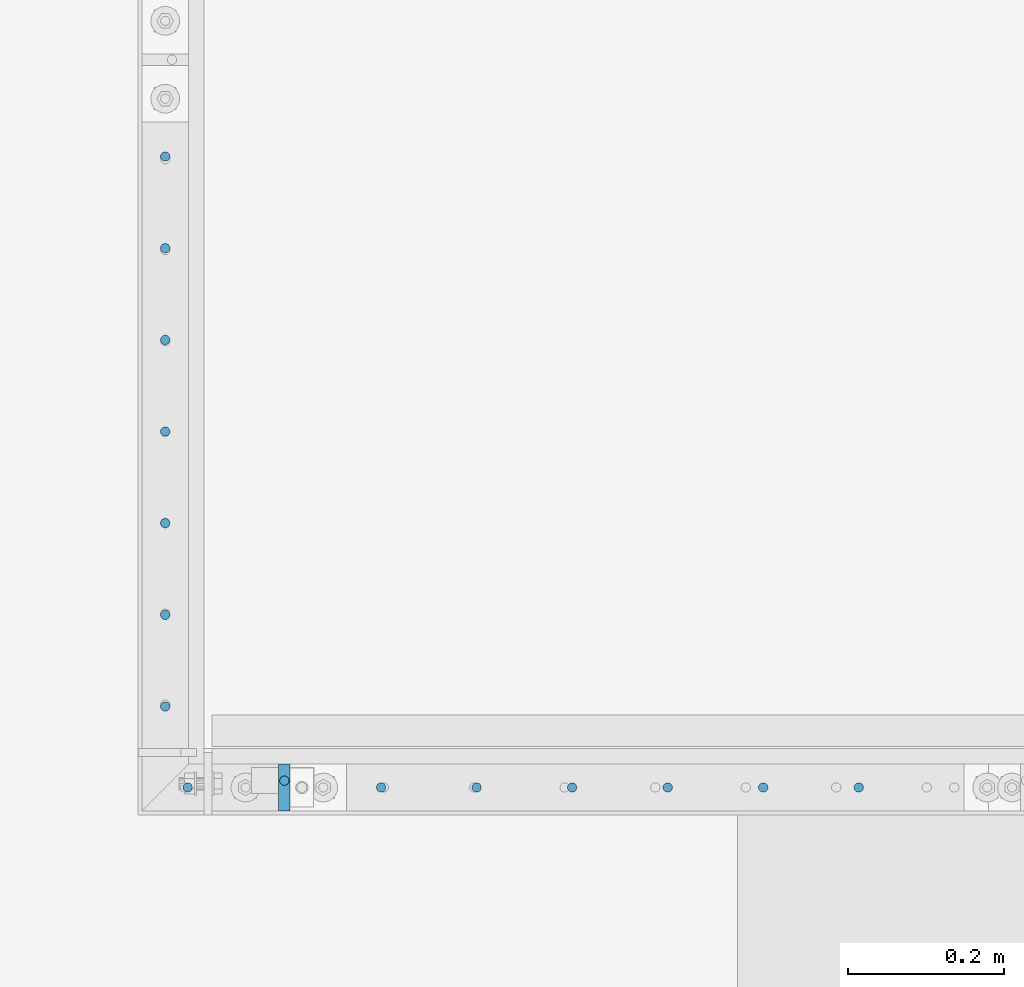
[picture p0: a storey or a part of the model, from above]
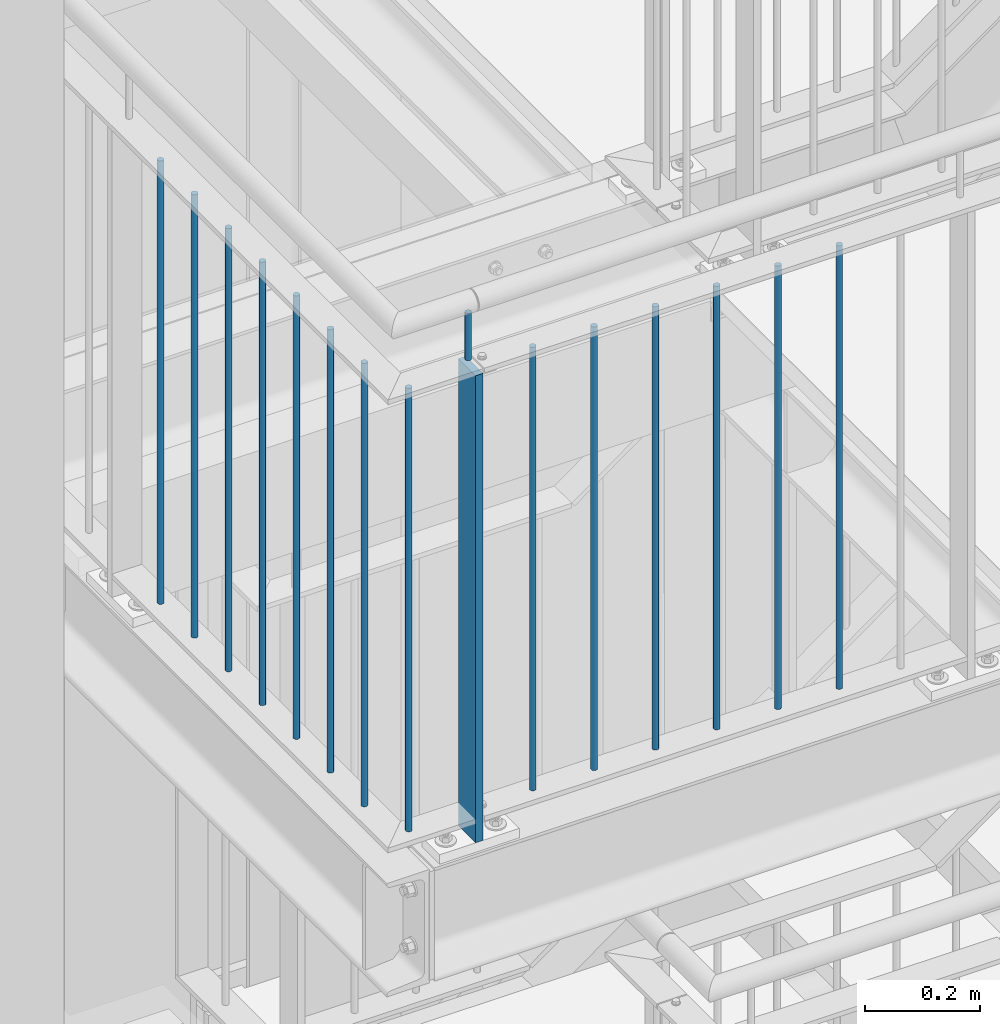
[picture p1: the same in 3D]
Properties of the parts of a building model (IFC2X3)

# File
Description: ViewDefinition[CoordinationView_V2.0]
File name: Treppenturm an Kinderklinik N?rnberg_ifc2x3.ifc
Time: 2026-07-12T00:24:05
Written by: IFC Toolkit 2.0.26.0
Made in: Advance Steel 2024

# IfcBuildingStorey, Default Storey
In: Struktur 1
Elevation: 0 mm

# IfcBeam: - (30)
In: Default Storey
Description: RO33.7X2.6; Material: S235JR
ProfileProperties - SectionFamily: Pipe nach DIN; Section: RO33.7X2.6

# IfcBeam: BottomLanding#1 (11)
In: Default Storey
Description: U240; Material: S235JR
ProfileProperties - SectionFamily: Channels DIN18800-1; Section: U240

# IfcBeam: BottomLanding#2 (11)
In: Default Storey
Description: U240; Material: S235JR
ProfileProperties - SectionFamily: Channels DIN18800-1; Section: U240

# IfcBeam: BottomLanding#3 (22)
In: Default Storey
Description: L40X4; Material: S235JR
ProfileProperties - SectionFamily: Angle_eq DIN18800-1; Section: L40X4

# IfcBeam: Elbow#0 (5)
In: Default Storey
Description: RO42.4X3.2; Material: S235JR

# IfcBeam: Elbow#1 (6)
In: Default Storey
Description: RO42.4X3.2; Material: S235JR

# IfcBeam: Gel?nder (13)
In: Default Storey
Description: RO42.4X3.2; Material: S235JR
Pset_BeamCommon - Slope: 0 deg; IsExternal: no; LoadBearing: no
ProfileProperties - SectionFamily: Pipe nach DIN; Section: RO42.4X3.2
Name | Reference | Span (mm)
Gel?nder | 80 | 2854.8
Gel?nder | 79 | 1242.04
5 x Gel?nder | 66 | 2854.8
5 x Gel?nder | 65 | 1242.04
Gel?nder | 93 | 1847

# IfcBeam: Girder (45)
In: Default Storey
Material: S235JR
Pset_BeamCommon - Slope: 0 deg; IsExternal: no; LoadBearing: no
Name | Description = Section | Reference | Span (mm) | SectionFamily
5 x Girder | U100 | 34 | 1139 | Channels DIN18800-1
Girder | IPE240 | 20 | 3963.5 | IPE DIN18800-1
Girder | U240 | 39 | 1605 | Channels DIN18800-1
Girder | U240 | 40 | 1260 | Channels DIN18800-1
11 x Girder | HEA200 | 17 | 2940 | HEA DIN18800-1
Girder | HEA200 | 18 | 2940 | HEA DIN18800-1
12 x Girder | RO82.5x3.2 (Mannesmann) | 21 | 3363.5 | Pipe nach mannesmann
5 x Girder | U240 | 35 | 3120 | Channels DIN18800-1
Girder | U240 | 37 | 2950 | Channels DIN18800-1
Girder | U240 | 38 | 2900 | Channels DIN18800-1
5 x Girder | U240 | 36 | 2900 | Channels DIN18800-1
Girder | IPE240 | 19 | 1596.75 | IPE DIN18800-1

# IfcBeam: Railing_Handrail_Landing#0 (7)
In: Default Storey
Description: RO42.4X3.2; Material: S235JR
ProfileProperties - SectionFamily: Pipe nach DIN; Section: RO42.4X3.2

# IfcBeam: Railing_Handrail_Landing#2 (16)
In: Default Storey
Description: RO42.4X3.2; Material: S235JR
ProfileProperties - SectionFamily: Pipe nach DIN; Section: RO42.4X3.2

# IfcBeam: Railing_Handrail_Landing#3 (3)
In: Default Storey
Description: RO42.4X3.2; Material: S235JR
ProfileProperties - SectionFamily: Pipe nach DIN; Section: RO42.4X3.2

# IfcBeam: Railing_Handrail_Landing#4 (24)
In: Default Storey
Description: RO42.4X3.2; Material: S235JR
ProfileProperties - SectionFamily: Pipe nach DIN; Section: RO42.4X3.2

# IfcBeam: Railing_Handrail_Landing#5 (22)
In: Default Storey
Description: RO42.4X3.2; Material: S235JR
ProfileProperties - SectionFamily: Pipe nach DIN; Section: RO42.4X3.2

# IfcBeam: Railing_Handrail_Landing#6 (10)
In: Default Storey
Description: RO42.4X3.2; Material: S235JR
ProfileProperties - SectionFamily: Pipe nach DIN; Section: RO42.4X3.2

# IfcBeam: Railing_Handrail_Landing#7 (2)
In: Default Storey
Description: RO42.4X3.2; Material: S235JR
ProfileProperties - SectionFamily: Pipe nach DIN; Section: RO42.4X3.2

# IfcBeam: Railing_Handrail_Landing#8 (10)
In: Default Storey
Description: RO42.4X3.2; Material: S235JR
ProfileProperties - SectionFamily: Pipe nach DIN; Section: RO42.4X3.2

# IfcBeam: Railing_Kneerail_Landing#0 (20)
In: Default Storey
Description: FL60X10; Material: S235JR
ProfileProperties - SectionFamily: Flat nach DIN; Section: FL60X10

# IfcBeam: Railing_Kneerail_Landing#1 (10)
In: Default Storey
Description: FL60X10; Material: S235JR
ProfileProperties - SectionFamily: Flat nach DIN; Section: FL60X10

# IfcBeam: Railing_Kneerail_Landing#10 (7)
In: Default Storey
Description: FL60X10; Material: S235JR
ProfileProperties - SectionFamily: Flat nach DIN; Section: FL60X10

# IfcBeam: Railing_Kneerail_Landing#1000 (12)
In: Default Storey
Description: FL60X10; Material: S235JR
ProfileProperties - SectionFamily: Flat nach DIN; Section: FL60X10

# IfcBeam: Railing_Kneerail_Landing#1001 (4)
In: Default Storey
Description: FL60X10; Material: S235JR
ProfileProperties - SectionFamily: Flat nach DIN; Section: FL60X10

# IfcBeam: Railing_Kneerail_Landing#1003
In: Default Storey
Description: FL60X10; Material: S235JR
ProfileProperties - SectionFamily: Flat nach DIN; Section: FL60X10

# IfcBeam: Railing_Kneerail_Landing#1004 (3)
In: Default Storey
Description: FL60X10; Material: S235JR
ProfileProperties - SectionFamily: Flat nach DIN; Section: FL60X10

# IfcBeam: Railing_Kneerail_Landing#1005 (21)
In: Default Storey
Description: FL60X10; Material: S235JR
ProfileProperties - SectionFamily: Flat nach DIN; Section: FL60X10

# IfcBeam: Railing_Kneerail_Landing#1006 (18)
In: Default Storey
Description: FL60X10; Material: S235JR
ProfileProperties - SectionFamily: Flat nach DIN; Section: FL60X10

# IfcBeam: Railing_Kneerail_Landing#1007 (6)
In: Default Storey
Description: FL60X10; Material: S235JR
ProfileProperties - SectionFamily: Flat nach DIN; Section: FL60X10

# IfcBeam: Railing_Kneerail_Landing#1008 (3)
In: Default Storey
Description: FL60X10; Material: S235JR
ProfileProperties - SectionFamily: Flat nach DIN; Section: FL60X10

# IfcBeam: Railing_Kneerail_Landing#1011 (3)
In: Default Storey
Description: FL60X10; Material: S235JR
ProfileProperties - SectionFamily: Flat nach DIN; Section: FL60X10

# IfcBeam: Railing_Kneerail_Landing#1012 (6)
In: Default Storey
Description: FL60X10; Material: S235JR
ProfileProperties - SectionFamily: Flat nach DIN; Section: FL60X10

# IfcBeam: Railing_Kneerail_Landing#1014 (4)
In: Default Storey
Description: FL60X10; Material: S235JR
ProfileProperties - SectionFamily: Flat nach DIN; Section: FL60X10

# IfcBeam: Railing_Kneerail_Landing#1018 (8)
In: Default Storey
Description: FL60X10; Material: S235JR
ProfileProperties - SectionFamily: Flat nach DIN; Section: FL60X10

# IfcBeam: Railing_Kneerail_Landing#1019
In: Default Storey
Description: FL60X10; Material: S235JR
ProfileProperties - SectionFamily: Flat nach DIN; Section: FL60X10

# IfcBeam: Railing_Kneerail_Landing#1020 (4)
In: Default Storey
Description: FL60X10; Material: S235JR
ProfileProperties - SectionFamily: Flat nach DIN; Section: FL60X10

# IfcBeam: Railing_Kneerail_Landing#1021 (5)
In: Default Storey
Description: FL60X10; Material: S235JR
ProfileProperties - SectionFamily: Flat nach DIN; Section: FL60X10

# IfcBeam: Railing_Kneerail_Landing#11 (6)
In: Default Storey
Description: FL60X10; Material: S235JR
ProfileProperties - SectionFamily: Flat nach DIN; Section: FL60X10

# IfcBeam: Railing_Kneerail_Landing#12 (5)
In: Default Storey
Description: FL60X10; Material: S235JR
ProfileProperties - SectionFamily: Flat nach DIN; Section: FL60X10

# IfcBeam: Railing_Kneerail_Landing#13 (5)
In: Default Storey
Description: FL60X10; Material: S235JR
ProfileProperties - SectionFamily: Flat nach DIN; Section: FL60X10

# IfcBeam: Railing_Kneerail_Landing#14 (4)
In: Default Storey
Description: FL60X10; Material: S235JR
ProfileProperties - SectionFamily: Flat nach DIN; Section: FL60X10

# IfcBeam: Railing_Kneerail_Landing#16
In: Default Storey
Description: FL60X10; Material: S235JR
ProfileProperties - SectionFamily: Flat nach DIN; Section: FL60X10

# IfcBeam: Railing_Kneerail_Landing#17
In: Default Storey
Description: FL60X10; Material: S235JR
ProfileProperties - SectionFamily: Flat nach DIN; Section: FL60X10

# IfcBeam: Railing_Kneerail_Landing#18 (6)
In: Default Storey
Description: FL60X10; Material: S235JR
ProfileProperties - SectionFamily: Flat nach DIN; Section: FL60X10

# IfcBeam: Railing_Kneerail_Landing#19 (6)
In: Default Storey
Description: FL60X10; Material: S235JR
ProfileProperties - SectionFamily: Flat nach DIN; Section: FL60X10

# IfcBeam: Railing_Kneerail_Landing#20 (5)
In: Default Storey
Description: FL60X10; Material: S235JR
ProfileProperties - SectionFamily: Flat nach DIN; Section: FL60X10

# IfcBeam: Railing_Kneerail_Landing#21 (5)
In: Default Storey
Description: FL60X10; Material: S235JR
ProfileProperties - SectionFamily: Flat nach DIN; Section: FL60X10

# IfcBeam: Railing_Kneerail_Landing#22 (6)
In: Default Storey
Description: FL60X10; Material: S235JR
ProfileProperties - SectionFamily: Flat nach DIN; Section: FL60X10

# IfcBeam: Railing_Kneerail_Landing#3
In: Default Storey
Description: FL60X10; Material: S235JR
ProfileProperties - SectionFamily: Flat nach DIN; Section: FL60X10

# IfcBeam: Railing_Kneerail_Landing#4 (10)
In: Default Storey
Description: FL60X10; Material: S235JR
ProfileProperties - SectionFamily: Flat nach DIN; Section: FL60X10

# IfcBeam: Railing_Kneerail_Landing#5 (19)
In: Default Storey
Description: FL60X10; Material: S235JR
ProfileProperties - SectionFamily: Flat nach DIN; Section: FL60X10

# IfcBeam: Railing_Kneerail_Landing#6 (24)
In: Default Storey
Description: FL60X10; Material: S235JR
ProfileProperties - SectionFamily: Flat nach DIN; Section: FL60X10

# IfcBeam: Railing_Kneerail_Landing#7 (13)
In: Default Storey
Description: FL60X10; Material: S235JR
ProfileProperties - SectionFamily: Flat nach DIN; Section: FL60X10

# IfcBeam: Railing_Kneerail_Landing#8 (7)
In: Default Storey
Description: FL60X10; Material: S235JR
ProfileProperties - SectionFamily: Flat nach DIN; Section: FL60X10

# IfcBeam: Railing_Kneerail_Landing#9 (6)
In: Default Storey
Description: FL60X10; Material: S235JR
ProfileProperties - SectionFamily: Flat nach DIN; Section: FL60X10

# IfcBeam: Stringer (24)
In: Default Storey
Description: U240; Material: S235JR
Pset_BeamCommon - Slope: 0 deg; IsExternal: no; LoadBearing: no
ProfileProperties - SectionFamily: Channels DIN18800-1; Section: U240
Name | Reference | Span (mm)
Stringer | 54 | 1960.42
Stringer | 53 | 1960.42
Stringer | 50 | 1960.32
Stringer | 49 | 1960.32
Stringer | 57 | 1960.25
Stringer | 58 | 1960.25
Stringer | 61 | 1960.57
Stringer | 62 | 1960.57
Stringer | 56 | 1960.42
Stringer | 55 | 1960.42
Stringer | 60 | 1960.25
Stringer | 59 | 1960.25
Stringer | 64 | 1960.57
Stringer | 63 | 1960.57
Stringer | 52 | 1960.32
Stringer | 51 | 1960.32
Stringer | 46 | 1441.89
Stringer | 45 | 1441.89
Stringer | 42 | 1441.18
Stringer | 41 | 1441.18
Stringer | 43 | 1961.18
Stringer | 44 | 1961.18
Stringer | 48 | 1961.89
Stringer | 47 | 1961.89

# IfcBeam: TopLanding#1 (5)
In: Default Storey
Description: U100; Material: S235JR
ProfileProperties - SectionFamily: Channels DIN18800-1; Section: U100

# IfcBeam: TopLanding#3 (24)
In: Default Storey
Description: L40X4; Material: S235JR
ProfileProperties - SectionFamily: Angle_eq DIN18800-1; Section: L40X4

# IfcBuildingElementProxy: - (216)
In: Default Storey
Material: Kein

# IfcColumn: - (4)
In: Default Storey
Description: HEA120; Material: S235JR
ProfileProperties - SectionFamily: HEA DIN18800-1; Section: HEA120

# IfcColumn: Bar#0 (18)
In: Default Storey
Description: RD12; Material: S235JR
ProfileProperties - SectionFamily: Round nach DIN; Section: RD12

# IfcColumn: Bar#1 (18)
In: Default Storey
Description: RD12; Material: S235JR
ProfileProperties - SectionFamily: Round nach DIN; Section: RD12

# IfcColumn: Bar#10 (6)
In: Default Storey
Description: RD12; Material: S235JR
ProfileProperties - SectionFamily: Round nach DIN; Section: RD12

# IfcColumn: Bar#11 (6)
In: Default Storey
Description: RD12; Material: S235JR
ProfileProperties - SectionFamily: Round nach DIN; Section: RD12

# IfcColumn: Bar#12 (6)
In: Default Storey
Description: RD12; Material: S235JR
ProfileProperties - SectionFamily: Round nach DIN; Section: RD12

# IfcColumn: Bar#13 (6)
In: Default Storey
Description: RD12; Material: S235JR
ProfileProperties - SectionFamily: Round nach DIN; Section: RD12

# IfcColumn: Bar#14 (5)
In: Default Storey
Description: RD12; Material: S235JR
ProfileProperties - SectionFamily: Round nach DIN; Section: RD12

# IfcColumn: Bar#2 (18)
In: Default Storey
Description: RD12; Material: S235JR
ProfileProperties - SectionFamily: Round nach DIN; Section: RD12

# IfcColumn: Bar#3 (10)
In: Default Storey
Description: RD12; Material: S235JR
ProfileProperties - SectionFamily: Round nach DIN; Section: RD12

# IfcColumn: Bar#4 (7)
In: Default Storey
Description: RD12; Material: S235JR
ProfileProperties - SectionFamily: Round nach DIN; Section: RD12

# IfcColumn: Bar#5 (6)
In: Default Storey
Description: RD12; Material: S235JR
ProfileProperties - SectionFamily: Round nach DIN; Section: RD12

# IfcColumn: Bar#6 (6)
In: Default Storey
Description: RD12; Material: S235JR
ProfileProperties - SectionFamily: Round nach DIN; Section: RD12

# IfcColumn: Bar#7 (6)
In: Default Storey
Description: RD12; Material: S235JR
ProfileProperties - SectionFamily: Round nach DIN; Section: RD12

# IfcColumn: Bar#8 (6)
In: Default Storey
Description: RD12; Material: S235JR
ProfileProperties - SectionFamily: Round nach DIN; Section: RD12

# IfcColumn: Bar#9 (6)
In: Default Storey
Description: RD12; Material: S235JR
ProfileProperties - SectionFamily: Round nach DIN; Section: RD12

# IfcColumn: Column (16)
In: Default Storey
Description: HEA200; Material: S235JR
Pset_ColumnCommon - Slope: 0 deg; IsExternal: no; LoadBearing: no
ProfileProperties - SectionFamily: HEA DIN18800-1; Section: HEA200
Name | Reference
Column | 2
Column | 1
Column | 3
Column | 4
Column | 5
Column | 6
Column | 7
Column | 8
Column | 9
Column | 10
Column | 11
Column | 12
Column | 13
Column | 14
Column | 15
Column | 16

# IfcColumn: Railing_Handrail_Landing#0 (2)
In: Default Storey
Description: RO42.4X3.2; Material: S235JR
ProfileProperties - SectionFamily: Pipe nach DIN; Section: RO42.4X3.2

# IfcColumn: Railing_Kneerail_Landing#0 (5)
In: Default Storey
Description: FL60X10; Material: S235JR
ProfileProperties - SectionFamily: Flat nach DIN; Section: FL60X10

# IfcColumn: Railing_Kneerail_Landing#22 (6)
In: Default Storey
Description: FL60X10; Material: S235JR
ProfileProperties - SectionFamily: Flat nach DIN; Section: FL60X10

# IfcColumn: Railing_Kneerail_Landing#8
In: Default Storey
Description: FL60X10; Material: S235JR
ProfileProperties - SectionFamily: Flat nach DIN; Section: FL60X10

# IfcColumn: Railing_Picket_Landing#0 (15)
In: Default Storey
Description: RD12; Material: S235JR
ProfileProperties - SectionFamily: Round nach DIN; Section: RD12

# IfcColumn: Railing_Picket_Landing#1 (8)
In: Default Storey
Description: RD12; Material: S235JR
ProfileProperties - SectionFamily: Round nach DIN; Section: RD12

# IfcColumn: Railing_Picket_Landing#12 (4)
In: Default Storey
Description: RD12; Material: S235JR
ProfileProperties - SectionFamily: Round nach DIN; Section: RD12

# IfcColumn: Railing_Picket_Landing#13 (4)
In: Default Storey
Description: RD12; Material: S235JR
ProfileProperties - SectionFamily: Round nach DIN; Section: RD12

# IfcColumn: Railing_Picket_Landing#14 (4)
In: Default Storey
Description: RD12; Material: S235JR
ProfileProperties - SectionFamily: Round nach DIN; Section: RD12

# IfcColumn: Railing_Picket_Landing#15 (5)
In: Default Storey
Description: RD12; Material: S235JR
ProfileProperties - SectionFamily: Round nach DIN; Section: RD12

# IfcColumn: Railing_Picket_Landing#16 (8)
In: Default Storey
Description: RD12; Material: S235JR
ProfileProperties - SectionFamily: Round nach DIN; Section: RD12

# IfcColumn: Railing_Picket_Landing#17 (8)
In: Default Storey
Description: RD12; Material: S235JR
ProfileProperties - SectionFamily: Round nach DIN; Section: RD12

# IfcColumn: Railing_Picket_Landing#18 (8)
In: Default Storey
Description: RD12; Material: S235JR
ProfileProperties - SectionFamily: Round nach DIN; Section: RD12

# IfcColumn: Railing_Picket_Landing#19 (8)
In: Default Storey
Description: RD12; Material: S235JR
ProfileProperties - SectionFamily: Round nach DIN; Section: RD12

# IfcColumn: Railing_Picket_Landing#2 (8)
In: Default Storey
Description: RD12; Material: S235JR
ProfileProperties - SectionFamily: Round nach DIN; Section: RD12

# IfcColumn: Railing_Picket_Landing#20 (9)
In: Default Storey
Description: RD12; Material: S235JR
ProfileProperties - SectionFamily: Round nach DIN; Section: RD12

# IfcColumn: Railing_Picket_Landing#21 (7)
In: Default Storey
Description: RD12; Material: S235JR
ProfileProperties - SectionFamily: Round nach DIN; Section: RD12

# IfcColumn: Railing_Picket_Landing#22 (7)
In: Default Storey
Description: RD12; Material: S235JR
ProfileProperties - SectionFamily: Round nach DIN; Section: RD12

# IfcColumn: Railing_Picket_Landing#23 (7)
In: Default Storey
Description: RD12; Material: S235JR
ProfileProperties - SectionFamily: Round nach DIN; Section: RD12

# IfcColumn: Railing_Picket_Landing#24 (7)
In: Default Storey
Description: RD12; Material: S235JR
ProfileProperties - SectionFamily: Round nach DIN; Section: RD12

# IfcColumn: Railing_Picket_Landing#25 (7)
In: Default Storey
Description: RD12; Material: S235JR
ProfileProperties - SectionFamily: Round nach DIN; Section: RD12

# IfcColumn: Railing_Picket_Landing#26 (7)
In: Default Storey
Description: RD12; Material: S235JR
ProfileProperties - SectionFamily: Round nach DIN; Section: RD12

# IfcColumn: Railing_Picket_Landing#27 (8)
In: Default Storey
Description: RD12; Material: S235JR
ProfileProperties - SectionFamily: Round nach DIN; Section: RD12

# IfcColumn: Railing_Picket_Landing#28 (6)
In: Default Storey
Description: RD12; Material: S235JR
ProfileProperties - SectionFamily: Round nach DIN; Section: RD12

# IfcColumn: Railing_Picket_Landing#29 (6)
In: Default Storey
Description: RD12; Material: S235JR
ProfileProperties - SectionFamily: Round nach DIN; Section: RD12

# IfcColumn: Railing_Picket_Landing#30 (6)
In: Default Storey
Description: RD12; Material: S235JR
ProfileProperties - SectionFamily: Round nach DIN; Section: RD12

# IfcColumn: Railing_Picket_Landing#31 (6)
In: Default Storey
Description: RD12; Material: S235JR
ProfileProperties - SectionFamily: Round nach DIN; Section: RD12

# IfcColumn: Railing_Picket_Landing#32 (6)
In: Default Storey
Description: RD12; Material: S235JR
ProfileProperties - SectionFamily: Round nach DIN; Section: RD12

# IfcColumn: Railing_Picket_Landing#33 (6)
In: Default Storey
Description: RD12; Material: S235JR
ProfileProperties - SectionFamily: Round nach DIN; Section: RD12

# IfcColumn: Railing_Picket_Landing#34 (6)
In: Default Storey
Description: RD12; Material: S235JR
ProfileProperties - SectionFamily: Round nach DIN; Section: RD12

# IfcColumn: Railing_Picket_Landing#35 (6)
In: Default Storey
Description: RD12; Material: S235JR
ProfileProperties - SectionFamily: Round nach DIN; Section: RD12

# IfcColumn: Railing_Picket_Landing#36 (6)
In: Default Storey
Description: RD12; Material: S235JR
ProfileProperties - SectionFamily: Round nach DIN; Section: RD12

# IfcColumn: Railing_Picket_Landing#37 (6)
In: Default Storey
Description: RD12; Material: S235JR
ProfileProperties - SectionFamily: Round nach DIN; Section: RD12

# IfcColumn: Railing_Picket_Landing#38 (6)
In: Default Storey
Description: RD12; Material: S235JR
ProfileProperties - SectionFamily: Round nach DIN; Section: RD12

# IfcColumn: Railing_Picket_Landing#39 (6)
In: Default Storey
Description: RD12; Material: S235JR
ProfileProperties - SectionFamily: Round nach DIN; Section: RD12

# IfcColumn: Railing_Picket_Landing#40 (6)
In: Default Storey
Description: RD12; Material: S235JR
ProfileProperties - SectionFamily: Round nach DIN; Section: RD12

# IfcColumn: Railing_Picket_Landing#41 (6)
In: Default Storey
Description: RD12; Material: S235JR
ProfileProperties - SectionFamily: Round nach DIN; Section: RD12

# IfcColumn: Railing_Picket_Landing#42 (6)
In: Default Storey
Description: RD12; Material: S235JR
ProfileProperties - SectionFamily: Round nach DIN; Section: RD12

# IfcColumn: Railing_Picket_Landing#43 (6)
In: Default Storey
Description: RD12; Material: S235JR
ProfileProperties - SectionFamily: Round nach DIN; Section: RD12

# IfcColumn: Railing_Picket_Landing#44 (6)
In: Default Storey
Description: RD12; Material: S235JR
ProfileProperties - SectionFamily: Round nach DIN; Section: RD12

# IfcColumn: Railing_Picket_Landing#45 (6)
In: Default Storey
Description: RD12; Material: S235JR
ProfileProperties - SectionFamily: Round nach DIN; Section: RD12

# IfcColumn: Railing_Picket_Landing#46 (6)
In: Default Storey
Description: RD12; Material: S235JR
ProfileProperties - SectionFamily: Round nach DIN; Section: RD12

# IfcColumn: Railing_Picket_Landing#47 (6)
In: Default Storey
Description: RD12; Material: S235JR
ProfileProperties - SectionFamily: Round nach DIN; Section: RD12

# IfcColumn: Railing_Picket_Landing#48 (6)
In: Default Storey
Description: RD12; Material: S235JR
ProfileProperties - SectionFamily: Round nach DIN; Section: RD12

# IfcColumn: Railing_Picket_Landing#49 (6)
In: Default Storey
Description: RD12; Material: S235JR
ProfileProperties - SectionFamily: Round nach DIN; Section: RD12

# IfcColumn: Railing_Picket_Landing#50 (6)
In: Default Storey
Description: RD12; Material: S235JR
ProfileProperties - SectionFamily: Round nach DIN; Section: RD12

# IfcColumn: Railing_Picket_Landing#51 (6)
In: Default Storey
Description: RD12; Material: S235JR
ProfileProperties - SectionFamily: Round nach DIN; Section: RD12

# IfcColumn: Railing_Picket_Landing#52 (6)
In: Default Storey
Description: RD12; Material: S235JR
ProfileProperties - SectionFamily: Round nach DIN; Section: RD12

# IfcColumn: Railing_Picket_Landing#53 (6)
In: Default Storey
Description: RD12; Material: S235JR
ProfileProperties - SectionFamily: Round nach DIN; Section: RD12

# IfcColumn: Railing_Picket_Landing#54 (6)
In: Default Storey
Description: RD12; Material: S235JR
ProfileProperties - SectionFamily: Round nach DIN; Section: RD12

# IfcColumn: Railing_Picket_Landing#55 (5)
In: Default Storey
Description: RD12; Material: S235JR
ProfileProperties - SectionFamily: Round nach DIN; Section: RD12

# IfcColumn: Railing_Picket_Landing#56 (5)
In: Default Storey
Description: RD12; Material: S235JR
ProfileProperties - SectionFamily: Round nach DIN; Section: RD12

# IfcColumn: Railing_Picket_Landing#57 (5)
In: Default Storey
Description: RD12; Material: S235JR
ProfileProperties - SectionFamily: Round nach DIN; Section: RD12

# IfcColumn: Railing_Picket_Landing#58 (5)
In: Default Storey
Description: RD12; Material: S235JR
ProfileProperties - SectionFamily: Round nach DIN; Section: RD12

# IfcColumn: Railing_Picket_Landing#59 (5)
In: Default Storey
Description: RD12; Material: S235JR
ProfileProperties - SectionFamily: Round nach DIN; Section: RD12

# IfcColumn: Railing_Picket_Landing#60 (4)
In: Default Storey
Description: RD12; Material: S235JR
ProfileProperties - SectionFamily: Round nach DIN; Section: RD12

# IfcColumn: Railing_Picket_Landing#61 (4)
In: Default Storey
Description: RD12; Material: S235JR
ProfileProperties - SectionFamily: Round nach DIN; Section: RD12

# IfcColumn: Railing_Picket_Landing#62 (4)
In: Default Storey
Description: RD12; Material: S235JR
ProfileProperties - SectionFamily: Round nach DIN; Section: RD12

# IfcColumn: Railing_Picket_Landing#70
In: Default Storey
Description: RD12; Material: S235JR
ProfileProperties - SectionFamily: Round nach DIN; Section: RD12

# IfcColumn: Railing_Picket_Landing#71
In: Default Storey
Description: RD12; Material: S235JR
ProfileProperties - SectionFamily: Round nach DIN; Section: RD12

# IfcColumn: Railing_Picket_Landing#72
In: Default Storey
Description: RD12; Material: S235JR
ProfileProperties - SectionFamily: Round nach DIN; Section: RD12

# IfcColumn: Railing_Picket_Landing#73
In: Default Storey
Description: RD12; Material: S235JR
ProfileProperties - SectionFamily: Round nach DIN; Section: RD12

# IfcColumn: Railing_Picket_Landing#74
In: Default Storey
Description: RD12; Material: S235JR
ProfileProperties - SectionFamily: Round nach DIN; Section: RD12

# IfcColumn: Railing_Picket_Landing#75
In: Default Storey
Description: RD12; Material: S235JR
ProfileProperties - SectionFamily: Round nach DIN; Section: RD12

# IfcColumn: Railing_Picket_Landing#76 (6)
In: Default Storey
Description: RD12; Material: S235JR
ProfileProperties - SectionFamily: Round nach DIN; Section: RD12

# IfcColumn: Railing_Picket_Landing#77 (6)
In: Default Storey
Description: RD12; Material: S235JR
ProfileProperties - SectionFamily: Round nach DIN; Section: RD12

# IfcColumn: Railing_Picket_Landing#78 (6)
In: Default Storey
Description: RD12; Material: S235JR
ProfileProperties - SectionFamily: Round nach DIN; Section: RD12

# IfcColumn: Railing_Picket_Landing#79 (6)
In: Default Storey
Description: RD12; Material: S235JR
ProfileProperties - SectionFamily: Round nach DIN; Section: RD12

# IfcColumn: Railing_Picket_Landing#80 (6)
In: Default Storey
Description: RD12; Material: S235JR
ProfileProperties - SectionFamily: Round nach DIN; Section: RD12

# IfcColumn: Railing_Picket_Landing#81 (6)
In: Default Storey
Description: RD12; Material: S235JR
ProfileProperties - SectionFamily: Round nach DIN; Section: RD12

# IfcColumn: Railing_Picket_Landing#82 (6)
In: Default Storey
Description: RD12; Material: S235JR
ProfileProperties - SectionFamily: Round nach DIN; Section: RD12

# IfcColumn: Railing_Picket_Landing#83 (6)
In: Default Storey
Description: RD12; Material: S235JR
ProfileProperties - SectionFamily: Round nach DIN; Section: RD12

# IfcColumn: Railing_Picket_Landing#84 (6)
In: Default Storey
Description: RD12; Material: S235JR
ProfileProperties - SectionFamily: Round nach DIN; Section: RD12

# IfcColumn: Railing_Picket_Landing#85 (6)
In: Default Storey
Description: RD12; Material: S235JR
ProfileProperties - SectionFamily: Round nach DIN; Section: RD12

# IfcColumn: Railing_Picket_Landing#86 (6)
In: Default Storey
Description: RD12; Material: S235JR
ProfileProperties - SectionFamily: Round nach DIN; Section: RD12

# IfcColumn: Railing_Picket_Landing#87 (6)
In: Default Storey
Description: RD12; Material: S235JR
ProfileProperties - SectionFamily: Round nach DIN; Section: RD12

# IfcColumn: Railing_Picket_Landing#88 (6)
In: Default Storey
Description: RD12; Material: S235JR
ProfileProperties - SectionFamily: Round nach DIN; Section: RD12

# IfcColumn: Railing_Picket_Landing#89 (6)
In: Default Storey
Description: RD12; Material: S235JR
ProfileProperties - SectionFamily: Round nach DIN; Section: RD12

# IfcColumn: Railing_Picket_Landing#90 (6)
In: Default Storey
Description: RD12; Material: S235JR
ProfileProperties - SectionFamily: Round nach DIN; Section: RD12

# IfcColumn: Railing_Picket_Landing#91 (6)
In: Default Storey
Description: RD12; Material: S235JR
ProfileProperties - SectionFamily: Round nach DIN; Section: RD12

# IfcColumn: Railing_Picket_Landing#92 (5)
In: Default Storey
Description: RD12; Material: S235JR
ProfileProperties - SectionFamily: Round nach DIN; Section: RD12

# IfcColumn: Railing_Picket_Landing#93 (5)
In: Default Storey
Description: RD12; Material: S235JR
ProfileProperties - SectionFamily: Round nach DIN; Section: RD12

# IfcColumn: Railing_Picket_Landing#94 (5)
In: Default Storey
Description: RD12; Material: S235JR
ProfileProperties - SectionFamily: Round nach DIN; Section: RD12

# IfcColumn: Railing_Picket_Landing#95 (5)
In: Default Storey
Description: RD12; Material: S235JR
ProfileProperties - SectionFamily: Round nach DIN; Section: RD12

# IfcColumn: Railing_Picket_Landing#96 (11)
In: Default Storey
Description: RD12; Material: S235JR
ProfileProperties - SectionFamily: Round nach DIN; Section: RD12

# IfcColumn: Railing_Picket_Landing#97 (11)
In: Default Storey
Description: RD12; Material: S235JR
ProfileProperties - SectionFamily: Round nach DIN; Section: RD12

# IfcColumn: Railing_Picket_Stair#0 (36)
In: Default Storey
Description: RD12; Material: S235JR
ProfileProperties - SectionFamily: Round nach DIN; Section: RD12

# IfcColumn: Railing_Picket_Stair#1 (10)
In: Default Storey
Description: RD12; Material: S235JR
ProfileProperties - SectionFamily: Round nach DIN; Section: RD12

# IfcColumn: Railing_Picket_Stair#10 (18)
In: Default Storey
Description: RD12; Material: S235JR
ProfileProperties - SectionFamily: Round nach DIN; Section: RD12

# IfcColumn: Railing_Picket_Stair#11 (18)
In: Default Storey
Description: RD12; Material: S235JR
ProfileProperties - SectionFamily: Round nach DIN; Section: RD12

# IfcColumn: Railing_Picket_Stair#12 (14)
In: Default Storey
Description: RD12; Material: S235JR
ProfileProperties - SectionFamily: Round nach DIN; Section: RD12

# IfcColumn: Railing_Picket_Stair#13 (14)
In: Default Storey
Description: RD12; Material: S235JR
ProfileProperties - SectionFamily: Round nach DIN; Section: RD12

# IfcColumn: Railing_Picket_Stair#14 (14)
In: Default Storey
Description: RD12; Material: S235JR
ProfileProperties - SectionFamily: Round nach DIN; Section: RD12

# IfcColumn: Railing_Picket_Stair#15 (13)
In: Default Storey
Description: RD12; Material: S235JR
ProfileProperties - SectionFamily: Round nach DIN; Section: RD12

# IfcColumn: Railing_Picket_Stair#16 (6)
In: Default Storey
Description: RD12; Material: S235JR
ProfileProperties - SectionFamily: Round nach DIN; Section: RD12

# IfcColumn: Railing_Picket_Stair#17 (6)
In: Default Storey
Description: RD12; Material: S235JR
ProfileProperties - SectionFamily: Round nach DIN; Section: RD12

# IfcColumn: Railing_Picket_Stair#18 (2)
In: Default Storey
Description: RD12; Material: S235JR
ProfileProperties - SectionFamily: Round nach DIN; Section: RD12

# IfcColumn: Railing_Picket_Stair#19 (2)
In: Default Storey
Description: RD12; Material: S235JR
ProfileProperties - SectionFamily: Round nach DIN; Section: RD12

# IfcColumn: Railing_Picket_Stair#2 (10)
In: Default Storey
Description: RD12; Material: S235JR
ProfileProperties - SectionFamily: Round nach DIN; Section: RD12

# IfcColumn: Railing_Picket_Stair#20
In: Default Storey
Description: RD12; Material: S235JR
ProfileProperties - SectionFamily: Round nach DIN; Section: RD12

# IfcColumn: Railing_Picket_Stair#3 (18)
In: Default Storey
Description: RD12; Material: S235JR
ProfileProperties - SectionFamily: Round nach DIN; Section: RD12

# IfcColumn: Railing_Picket_Stair#4 (18)
In: Default Storey
Description: RD12; Material: S235JR
ProfileProperties - SectionFamily: Round nach DIN; Section: RD12

# IfcColumn: Railing_Picket_Stair#5 (18)
In: Default Storey
Description: RD12; Material: S235JR
ProfileProperties - SectionFamily: Round nach DIN; Section: RD12

# IfcColumn: Railing_Picket_Stair#55
In: Default Storey
Description: RD12; Material: S235JR
ProfileProperties - SectionFamily: Round nach DIN; Section: RD12

# IfcColumn: Railing_Picket_Stair#56
In: Default Storey
Description: RD12; Material: S235JR
ProfileProperties - SectionFamily: Round nach DIN; Section: RD12

# IfcColumn: Railing_Picket_Stair#57
In: Default Storey
Description: RD12; Material: S235JR
ProfileProperties - SectionFamily: Round nach DIN; Section: RD12

# IfcColumn: Railing_Picket_Stair#58
In: Default Storey
Description: RD12; Material: S235JR
ProfileProperties - SectionFamily: Round nach DIN; Section: RD12

# IfcColumn: Railing_Picket_Stair#59
In: Default Storey
Description: RD12; Material: S235JR
ProfileProperties - SectionFamily: Round nach DIN; Section: RD12

# IfcColumn: Railing_Picket_Stair#6 (18)
In: Default Storey
Description: RD12; Material: S235JR
ProfileProperties - SectionFamily: Round nach DIN; Section: RD12

# IfcColumn: Railing_Picket_Stair#60 (2)
In: Default Storey
Description: RD12; Material: S235JR
ProfileProperties - SectionFamily: Round nach DIN; Section: RD12

# IfcColumn: Railing_Picket_Stair#61 (2)
In: Default Storey
Description: RD12; Material: S235JR
ProfileProperties - SectionFamily: Round nach DIN; Section: RD12

# IfcColumn: Railing_Picket_Stair#62 (2)
In: Default Storey
Description: RD12; Material: S235JR
ProfileProperties - SectionFamily: Round nach DIN; Section: RD12

# IfcColumn: Railing_Picket_Stair#63 (6)
In: Default Storey
Description: RD12; Material: S235JR
ProfileProperties - SectionFamily: Round nach DIN; Section: RD12

# IfcColumn: Railing_Picket_Stair#64 (6)
In: Default Storey
Description: RD12; Material: S235JR
ProfileProperties - SectionFamily: Round nach DIN; Section: RD12

# IfcColumn: Railing_Picket_Stair#65 (6)
In: Default Storey
Description: RD12; Material: S235JR
ProfileProperties - SectionFamily: Round nach DIN; Section: RD12

# IfcColumn: Railing_Picket_Stair#66 (6)
In: Default Storey
Description: RD12; Material: S235JR
ProfileProperties - SectionFamily: Round nach DIN; Section: RD12

# IfcColumn: Railing_Picket_Stair#67 (6)
In: Default Storey
Description: RD12; Material: S235JR
ProfileProperties - SectionFamily: Round nach DIN; Section: RD12

# IfcColumn: Railing_Picket_Stair#68 (6)
In: Default Storey
Description: RD12; Material: S235JR
ProfileProperties - SectionFamily: Round nach DIN; Section: RD12

# IfcColumn: Railing_Picket_Stair#69 (6)
In: Default Storey
Description: RD12; Material: S235JR
ProfileProperties - SectionFamily: Round nach DIN; Section: RD12

# IfcColumn: Railing_Picket_Stair#7 (20)
In: Default Storey
Description: RD12; Material: S235JR
ProfileProperties - SectionFamily: Round nach DIN; Section: RD12

# IfcColumn: Railing_Picket_Stair#70 (5)
In: Default Storey
Description: RD12; Material: S235JR
ProfileProperties - SectionFamily: Round nach DIN; Section: RD12

# IfcColumn: Railing_Picket_Stair#71 (5)
In: Default Storey
Description: RD12; Material: S235JR
ProfileProperties - SectionFamily: Round nach DIN; Section: RD12

# IfcColumn: Railing_Picket_Stair#72 (5)
In: Default Storey
Description: RD12; Material: S235JR
ProfileProperties - SectionFamily: Round nach DIN; Section: RD12

# IfcColumn: Railing_Picket_Stair#73 (5)
In: Default Storey
Description: RD12; Material: S235JR
ProfileProperties - SectionFamily: Round nach DIN; Section: RD12

# IfcColumn: Railing_Picket_Stair#74 (5)
In: Default Storey
Description: RD12; Material: S235JR
ProfileProperties - SectionFamily: Round nach DIN; Section: RD12

# IfcColumn: Railing_Picket_Stair#75 (5)
In: Default Storey
Description: RD12; Material: S235JR
ProfileProperties - SectionFamily: Round nach DIN; Section: RD12

# IfcColumn: Railing_Picket_Stair#8 (18)
In: Default Storey
Description: RD12; Material: S235JR
ProfileProperties - SectionFamily: Round nach DIN; Section: RD12

# IfcColumn: Railing_Picket_Stair#9 (18)
In: Default Storey
Description: RD12; Material: S235JR
ProfileProperties - SectionFamily: Round nach DIN; Section: RD12

# IfcColumn: Railing_Post_Landing#0 (10)
In: Default Storey
Description: FL60X15; Material: S235JR
ProfileProperties - SectionFamily: Flat nach DIN; Section: FL60X15

# IfcColumn: Railing_Post_Landing#11
In: Default Storey
Description: FL60X15; Material: S235JR
ProfileProperties - SectionFamily: Flat nach DIN; Section: FL60X15

# IfcColumn: Railing_Post_Landing#12 (6)
In: Default Storey
Description: FL60X15; Material: S235JR
ProfileProperties - SectionFamily: Flat nach DIN; Section: FL60X15

# IfcColumn: Railing_Post_Landing#13 (6)
In: Default Storey
Description: FL60X15; Material: S235JR
ProfileProperties - SectionFamily: Flat nach DIN; Section: FL60X15

# IfcColumn: Railing_Post_Landing#14 (5)
In: Default Storey
Description: FL60X15; Material: S235JR
ProfileProperties - SectionFamily: Flat nach DIN; Section: FL60X15

# IfcColumn: Railing_Post_Landing#2 (9)
In: Default Storey
Description: FL60X15; Material: S235JR
ProfileProperties - SectionFamily: Flat nach DIN; Section: FL60X15

# IfcColumn: Railing_Post_Landing#3 (10)
In: Default Storey
Description: FL60X15; Material: S235JR
ProfileProperties - SectionFamily: Flat nach DIN; Section: FL60X15

# IfcColumn: Railing_Post_Landing#4 (7)
In: Default Storey
Description: FL60X15; Material: S235JR
ProfileProperties - SectionFamily: Flat nach DIN; Section: FL60X15

# IfcColumn: Railing_Post_Landing#5 (6)
In: Default Storey
Description: FL60X15; Material: S235JR
ProfileProperties - SectionFamily: Flat nach DIN; Section: FL60X15

# IfcColumn: Railing_Post_Landing#6 (6)
In: Default Storey
Description: FL60X15; Material: S235JR
ProfileProperties - SectionFamily: Flat nach DIN; Section: FL60X15

# IfcColumn: Railing_Post_Landing#7 (6)
In: Default Storey
Description: FL60X15; Material: S235JR
ProfileProperties - SectionFamily: Flat nach DIN; Section: FL60X15

# IfcColumn: Railing_Post_Landing#8 (5)
In: Default Storey
Description: FL60X15; Material: S235JR
ProfileProperties - SectionFamily: Flat nach DIN; Section: FL60X15

# IfcColumn: Railing_Post_Landing#9 (4)
In: Default Storey
Description: FL60X15; Material: S235JR
ProfileProperties - SectionFamily: Flat nach DIN; Section: FL60X15

# IfcColumn: Railing_Post_Stair#0 (10)
In: Default Storey
Material: S235JR
ProfileProperties - SectionFamily: Flat nach DIN
Name | Description = Section
2 x Railing_Post_Stair#0 | FL60X10
8 x Railing_Post_Stair#0 | FL60X15

# IfcColumn: Railing_Post_Stair#1 (18)
In: Default Storey
Description: FL60X15; Material: S235JR
ProfileProperties - SectionFamily: Flat nach DIN; Section: FL60X15

# IfcColumn: Railing_Post_Stair#10 (6)
In: Default Storey
Description: FL60X15; Material: S235JR
ProfileProperties - SectionFamily: Flat nach DIN; Section: FL60X15

# IfcColumn: Railing_Post_Stair#11 (5)
In: Default Storey
Description: FL60X15; Material: S235JR
ProfileProperties - SectionFamily: Flat nach DIN; Section: FL60X15

# IfcColumn: Railing_Post_Stair#2 (9)
In: Default Storey
Description: FL60X15; Material: S235JR
ProfileProperties - SectionFamily: Flat nach DIN; Section: FL60X15

# IfcColumn: Railing_Post_Stair#8
In: Default Storey
Description: FL60X15; Material: S235JR
ProfileProperties - SectionFamily: Flat nach DIN; Section: FL60X15

# IfcColumn: Railing_Post_Stair#9 (2)
In: Default Storey
Description: FL60X15; Material: S235JR
ProfileProperties - SectionFamily: Flat nach DIN; Section: FL60X15

# IfcColumn: Stringer (2)
In: Default Storey
Description: U240; Material: S235JR
ProfileProperties - SectionFamily: Channels DIN18800-1; Section: U240

# IfcFooting: Foundation (2)
In: Default Storey
Description: -; Material: C20/25 1300 mm

# IfcMechanicalFastener: - (145)
In: Default Storey
Name | NominalDiameter (mm) | NominalLength (mm)
60 x  | 8 | 30
10 x  | 12 | 40
3 x  | 12 | 45
48 x  | 16 | 65
24 x  | 16 | 55

# IfcMechanicalFastener: Anchor_Bolt (2)
In: Default Storey
NominalDiameter: 16 mm; NominalLength: 220 mm

# IfcMechanicalFastener: Bolt (420)
In: Default Storey
NominalDiameter: 12 mm
Name | NominalLength (mm)
328 x  | 35
92 x  | 45

# IfcMechanicalFastener: Bolt#1 (38)
In: Default Storey
Name | NominalDiameter (mm) | NominalLength (mm)
 | 16 | 55
24 x  | 16 | 45
12 x  | 20 | 85
 | 16 | 75

# IfcMechanicalFastener: Bolt#2 (86)
In: Default Storey
Name | NominalDiameter (mm) | NominalLength (mm)
 | 16 | 55
72 x  | 16 | 45
12 x  | 20 | 85
 | 16 | 75

# IfcMechanicalFastener: Bolt#3 (2)
In: Default Storey
NominalDiameter: 16 mm
Name | NominalLength (mm)
 | 55
 | 75

# IfcMechanicalFastener: Bolt#4 (2)
In: Default Storey
NominalDiameter: 16 mm
Name | NominalLength (mm)
 | 55
 | 75

# IfcMechanicalFastener: Bolt#5 (26)
In: Default Storey
NominalDiameter: 16 mm
Name | NominalLength (mm)
 | 55
24 x  | 45
 | 75

# IfcMechanicalFastener: Bolt#500 (18)
In: Default Storey
NominalDiameter: 12 mm; NominalLength: 55 mm

# IfcMechanicalFastener: Bolt#501 (18)
In: Default Storey
NominalDiameter: 12 mm; NominalLength: 55 mm

# IfcMechanicalFastener: Bolt#502 (18)
In: Default Storey
NominalDiameter: 12 mm; NominalLength: 55 mm

# IfcMechanicalFastener: Bolt#503 (10)
In: Default Storey
NominalDiameter: 12 mm; NominalLength: 55 mm

# IfcMechanicalFastener: Bolt#504 (7)
In: Default Storey
NominalDiameter: 12 mm; NominalLength: 55 mm

# IfcMechanicalFastener: Bolt#505 (6)
In: Default Storey
NominalDiameter: 12 mm; NominalLength: 55 mm

# IfcMechanicalFastener: Bolt#506 (6)
In: Default Storey
NominalDiameter: 12 mm; NominalLength: 55 mm

# IfcMechanicalFastener: Bolt#507 (6)
In: Default Storey
NominalDiameter: 12 mm; NominalLength: 55 mm

# IfcMechanicalFastener: Bolt#508 (6)
In: Default Storey
NominalDiameter: 12 mm; NominalLength: 55 mm

# IfcMechanicalFastener: Bolt#509 (6)
In: Default Storey
NominalDiameter: 12 mm; NominalLength: 55 mm

# IfcMechanicalFastener: Bolt#510 (6)
In: Default Storey
NominalDiameter: 12 mm; NominalLength: 55 mm

# IfcMechanicalFastener: Bolt#511 (6)
In: Default Storey
NominalDiameter: 12 mm; NominalLength: 55 mm

# IfcMechanicalFastener: Bolt#512 (6)
In: Default Storey
NominalDiameter: 12 mm; NominalLength: 55 mm

# IfcMechanicalFastener: Bolt#513 (6)
In: Default Storey
NominalDiameter: 12 mm; NominalLength: 55 mm

# IfcMechanicalFastener: Bolt#514 (5)
In: Default Storey
NominalDiameter: 12 mm; NominalLength: 55 mm

# IfcMechanicalFastener: Bolt#6 (26)
In: Default Storey
NominalDiameter: 16 mm
Name | NominalLength (mm)
 | 55
24 x  | 45
 | 75

# IfcMember: - (48)
In: Default Storey
Description: RD22; Material: S235JR
ProfileProperties - SectionFamily: Round nach DIN; Section: RD22
Name
2 x - | Pset_MemberCommon - Reference: 22; Span: 3558.71 mm; Slope: 0 deg; IsExternal: no; LoadBearing: no
24 x -
2 x - | Pset_MemberCommon - Reference: 26; Span: 3152.49 mm; Slope: 0 deg; IsExternal: no; LoadBearing: no
2 x - | Pset_MemberCommon - Reference: 24; Span: 3695.89 mm; Slope: 0 deg; IsExternal: no; LoadBearing: no
2 x - | Pset_MemberCommon - Reference: 23; Span: 3558.71 mm; Slope: 0 deg; IsExternal: no; LoadBearing: no
2 x - | Pset_MemberCommon - Reference: 25; Span: 3695.89 mm; Slope: 0 deg; IsExternal: no; LoadBearing: no
2 x - | Pset_MemberCommon - Reference: 27; Span: 3152.49 mm; Slope: 0 deg; IsExternal: no; LoadBearing: no
2 x - | Pset_MemberCommon - Reference: 28; Span: 3149.75 mm; Slope: 0 deg; IsExternal: no; LoadBearing: no
2 x - | Pset_MemberCommon - Reference: 29; Span: 3149.75 mm; Slope: 0 deg; IsExternal: no; LoadBearing: no
2 x - | Pset_MemberCommon - Reference: 30; Span: 3154.14 mm; Slope: 0 deg; IsExternal: no; LoadBearing: no
2 x - | Pset_MemberCommon - Reference: 31; Span: 3154.14 mm; Slope: 0 deg; IsExternal: no; LoadBearing: no
2 x - | Pset_MemberCommon - Reference: 32; Span: 3145.92 mm; Slope: 0 deg; IsExternal: no; LoadBearing: no
2 x - | Pset_MemberCommon - Reference: 33; Span: 3145.92 mm; Slope: 0 deg; IsExternal: no; LoadBearing: no

# IfcMember: Gel?nder (24)
In: Default Storey
Description: RO42.4X3.2; Material: S235JR
Pset_MemberCommon - Slope: 0 deg; IsExternal: no; LoadBearing: no
ProfileProperties - SectionFamily: Pipe nach DIN; Section: RO42.4X3.2
Name | Reference | Span (mm)
Gel?nder | 78 | 3228.48
Gel?nder | 77 | 2886
Gel?nder | 76 | 3191.65
Gel?nder | 75 | 2873.83
Gel?nder | 74 | 2259.66
Gel?nder | 73 | 2259.66
Gel?nder | 72 | 2258.18
Gel?nder | 71 | 2258.18
Gel?nder | 69 | 2260.56
Gel?nder | 70 | 2260.56
Gel?nder | 68 | 2256.1
Gel?nder | 67 | 2256.1
Gel?nder | 81 | 3228.48
Gel?nder | 83 | 3191.65
Gel?nder | 85 | 2259.66
Gel?nder | 87 | 2258.18
Gel?nder | 89 | 2260.56
Gel?nder | 91 | 2256.1
Gel?nder | 82 | 2886
Gel?nder | 84 | 2873.83
Gel?nder | 86 | 2259.66
Gel?nder | 88 | 2258.18
Gel?nder | 90 | 2260.56
Gel?nder | 92 | 2256.1

# IfcMember: Railing_Kneerail_Stair#1 (10)
In: Default Storey
Description: FL60X10; Material: S235JR
ProfileProperties - SectionFamily: Flat nach DIN; Section: FL60X10

# IfcMember: Railing_Kneerail_Stair#1000 (2)
In: Default Storey
Description: FL60X10; Material: S235JR
ProfileProperties - SectionFamily: Flat nach DIN; Section: FL60X10

# IfcMember: Railing_Kneerail_Stair#1001
In: Default Storey
Description: FL60X10; Material: S235JR
ProfileProperties - SectionFamily: Flat nach DIN; Section: FL60X10

# IfcMember: Railing_Kneerail_Stair#1002 (5)
In: Default Storey
Description: FL60X10; Material: S235JR
ProfileProperties - SectionFamily: Flat nach DIN; Section: FL60X10

# IfcMember: Railing_Kneerail_Stair#1003 (7)
In: Default Storey
Description: FL60X10; Material: S235JR
ProfileProperties - SectionFamily: Flat nach DIN; Section: FL60X10

# IfcMember: Railing_Kneerail_Stair#1004 (3)
In: Default Storey
Description: FL60X10; Material: S235JR
ProfileProperties - SectionFamily: Flat nach DIN; Section: FL60X10

# IfcMember: Railing_Kneerail_Stair#1014
In: Default Storey
Description: FL60X10; Material: S235JR
ProfileProperties - SectionFamily: Flat nach DIN; Section: FL60X10

# IfcMember: Railing_Kneerail_Stair#1015 (4)
In: Default Storey
Description: FL60X10; Material: S235JR
ProfileProperties - SectionFamily: Flat nach DIN; Section: FL60X10

# IfcMember: Railing_Kneerail_Stair#1017
In: Default Storey
Description: FL60X10; Material: S235JR
ProfileProperties - SectionFamily: Flat nach DIN; Section: FL60X10

# IfcMember: Railing_Kneerail_Stair#12
In: Default Storey
Description: FL60X10; Material: S235JR
ProfileProperties - SectionFamily: Flat nach DIN; Section: FL60X10

# IfcMember: Railing_Kneerail_Stair#13
In: Default Storey
Description: FL60X10; Material: S235JR
ProfileProperties - SectionFamily: Flat nach DIN; Section: FL60X10

# IfcMember: Railing_Kneerail_Stair#14 (2)
In: Default Storey
Description: FL60X10; Material: S235JR
ProfileProperties - SectionFamily: Flat nach DIN; Section: FL60X10

# IfcMember: Railing_Kneerail_Stair#15 (6)
In: Default Storey
Description: FL60X10; Material: S235JR
ProfileProperties - SectionFamily: Flat nach DIN; Section: FL60X10

# IfcMember: Railing_Kneerail_Stair#16 (5)
In: Default Storey
Description: FL60X10; Material: S235JR
ProfileProperties - SectionFamily: Flat nach DIN; Section: FL60X10

# IfcMember: Railing_Kneerail_Stair#17 (5)
In: Default Storey
Description: FL60X10; Material: S235JR
ProfileProperties - SectionFamily: Flat nach DIN; Section: FL60X10

# IfcMember: Railing_Kneerail_Stair#2 (18)
In: Default Storey
Description: FL60X10; Material: S235JR
ProfileProperties - SectionFamily: Flat nach DIN; Section: FL60X10

# IfcMember: Railing_Kneerail_Stair#3 (17)
In: Default Storey
Description: FL60X10; Material: S235JR
ProfileProperties - SectionFamily: Flat nach DIN; Section: FL60X10

# IfcMember: Railing_Kneerail_Stair#4 (8)
In: Default Storey
Description: FL60X10; Material: S235JR
ProfileProperties - SectionFamily: Flat nach DIN; Section: FL60X10

# IfcMember: Stringer#1 (12)
In: Default Storey
Description: U240; Material: S235JR
ProfileProperties - SectionFamily: Channels DIN18800-1; Section: U240

# IfcMember: Stringer#2 (12)
In: Default Storey
Description: U240; Material: S235JR
ProfileProperties - SectionFamily: Channels DIN18800-1; Section: U240

# IfcPlate: - (325)
In: Default Storey
Description: -
Pset_PlateCommon - IsExternal: no; LoadBearing: no
Name | Material | Reference
8 x - | S235JR 12 mm | 117
- | S235JR 30 mm | 319
4 x - | S235JR 20 mm | 308
3 x - | S235JR 30 mm | 309
12 x - | S235JR 3 mm | 547
38 x - | S235JR 6 mm | 545
22 x - | S235JR 6 mm | 546
10 x - | S235JR 10 mm | 344
2 x - | S235JR 15 mm | 323
- | S235JR 15 mm | 398
10 x - | S235JR 15 mm | 396
4 x - | S235JR 10 mm | 307
- | S235JR 20 mm | 318
2 x - | S235JR 20 mm | 314
6 x - | S235JR 20 mm | 306
2 x - | S235JR 20 mm | 312
48 x - | S235JR 20 mm | 335
24 x - | S235JR 10 mm | 324
- | S235JR 20 mm | 315
2 x - | S235JR 20 mm | 313
6 x - | S235JR 20 mm | 305
2 x - | S235JR 20 mm | 311
- | S235JR 20 mm | 316
48 x - | S235JR 15 mm | 112
12 x - | S235JR 10 mm | 116
40 x - | S235JR 10 mm | 302
12 x - | S235JR 20 mm | 304
2 x - | S235JR 10 mm | 310
- | S235JR 20 mm | 317

# IfcPlate: Baseplate (2)
In: Default Storey
Description: -; Material: S235JR 20 mm
Pset_PlateCommon - Reference: 397; IsExternal: no; LoadBearing: no

# IfcPlate: BottomCoverGrate (22)
In: Default Storey
Description: -; Material: S235JR 40 mm
Pset_PlateCommon - IsExternal: no; LoadBearing: no
Name | Reference
5 x BottomCoverGrate | 96
4 x BottomCoverGrate | 98
BottomCoverGrate | 109
2 x BottomCoverGrate | 104
2 x BottomCoverGrate | 105
4 x BottomCoverGrate | 102
4 x BottomCoverGrate | 101

# IfcPlate: Endplate (75)
In: Default Storey
Description: -
Pset_PlateCommon - IsExternal: no; LoadBearing: no
Name | Material | Reference
3 x Endplate | S235JR 20 mm | 322
24 x Endplate | S235JR 10 mm | 321
48 x Endplate | S235JR 10 mm | 394

# IfcPlate: Endplate#1 (12)
In: Default Storey
Description: -; Material: S235JR 25 mm
Pset_PlateCommon - Reference: 303; IsExternal: no; LoadBearing: no

# IfcPlate: Endplate#2 (12)
In: Default Storey
Description: -; Material: S235JR 25 mm
Pset_PlateCommon - Reference: 303; IsExternal: no; LoadBearing: no

# IfcPlate: Grate_Step#1 (12)
In: Default Storey
Description: -; Material: S235JR 40 mm
Pset_PlateCommon - Reference: 94; IsExternal: no; LoadBearing: no

# IfcPlate: Grate_Step#10 (12)
In: Default Storey
Description: -; Material: S235JR 3 mm
Pset_PlateCommon - Reference: 602; IsExternal: no; LoadBearing: no

# IfcPlate: Grate_Step#15 (12)
In: Default Storey
Description: -; Material: S235JR 40 mm
Pset_PlateCommon - Reference: 94; IsExternal: no; LoadBearing: no

# IfcPlate: Grate_Step#16 (12)
In: Default Storey
Description: -; Material: S235JR 3 mm
Pset_PlateCommon - Reference: 602; IsExternal: no; LoadBearing: no

# IfcPlate: Grate_Step#17 (12)
In: Default Storey
Description: -; Material: S235JR 3 mm
Pset_PlateCommon - Reference: 602; IsExternal: no; LoadBearing: no

# IfcPlate: Grate_Step#2 (12)
In: Default Storey
Description: -; Material: S235JR 3 mm
Pset_PlateCommon - Reference: 602; IsExternal: no; LoadBearing: no

# IfcPlate: Grate_Step#22 (12)
In: Default Storey
Description: -; Material: S235JR 40 mm
Pset_PlateCommon - Reference: 94; IsExternal: no; LoadBearing: no

# IfcPlate: Grate_Step#23 (12)
In: Default Storey
Description: -; Material: S235JR 3 mm
Pset_PlateCommon - Reference: 602; IsExternal: no; LoadBearing: no

# IfcPlate: Grate_Step#24 (12)
In: Default Storey
Description: -; Material: S235JR 3 mm
Pset_PlateCommon - Reference: 602; IsExternal: no; LoadBearing: no

# IfcPlate: Grate_Step#29 (12)
In: Default Storey
Description: -; Material: S235JR 40 mm
Pset_PlateCommon - Reference: 94; IsExternal: no; LoadBearing: no

# IfcPlate: Grate_Step#3 (12)
In: Default Storey
Description: -; Material: S235JR 3 mm
Pset_PlateCommon - Reference: 602; IsExternal: no; LoadBearing: no

# IfcPlate: Grate_Step#30 (12)
In: Default Storey
Description: -; Material: S235JR 3 mm
Pset_PlateCommon - Reference: 602; IsExternal: no; LoadBearing: no

# IfcPlate: Grate_Step#31 (12)
In: Default Storey
Description: -; Material: S235JR 3 mm
Pset_PlateCommon - Reference: 602; IsExternal: no; LoadBearing: no

# IfcPlate: Grate_Step#36 (12)
In: Default Storey
Description: -; Material: S235JR 40 mm
Pset_PlateCommon - Reference: 94; IsExternal: no; LoadBearing: no

# IfcPlate: Grate_Step#37 (12)
In: Default Storey
Description: -; Material: S235JR 3 mm
Pset_PlateCommon - Reference: 602; IsExternal: no; LoadBearing: no

# IfcPlate: Grate_Step#38 (12)
In: Default Storey
Description: -; Material: S235JR 3 mm
Pset_PlateCommon - Reference: 602; IsExternal: no; LoadBearing: no

# IfcPlate: Grate_Step#43 (4)
In: Default Storey
Description: -; Material: S235JR 40 mm
Pset_PlateCommon - Reference: 94; IsExternal: no; LoadBearing: no

# IfcPlate: Grate_Step#44 (4)
In: Default Storey
Description: -; Material: S235JR 3 mm
Pset_PlateCommon - Reference: 602; IsExternal: no; LoadBearing: no

# IfcPlate: Grate_Step#45 (4)
In: Default Storey
Description: -; Material: S235JR 3 mm
Pset_PlateCommon - Reference: 602; IsExternal: no; LoadBearing: no

# IfcPlate: Grate_Step#50 (4)
In: Default Storey
Description: -; Material: S235JR 40 mm
Pset_PlateCommon - Reference: 94; IsExternal: no; LoadBearing: no

# IfcPlate: Grate_Step#51 (4)
In: Default Storey
Description: -; Material: S235JR 3 mm
Pset_PlateCommon - Reference: 602; IsExternal: no; LoadBearing: no

# IfcPlate: Grate_Step#52 (4)
In: Default Storey
Description: -; Material: S235JR 3 mm
Pset_PlateCommon - Reference: 602; IsExternal: no; LoadBearing: no

# IfcPlate: Grate_Step#57 (2)
In: Default Storey
Description: -; Material: S235JR 40 mm
Pset_PlateCommon - Reference: 94; IsExternal: no; LoadBearing: no

# IfcPlate: Grate_Step#58 (2)
In: Default Storey
Description: -; Material: S235JR 3 mm
Pset_PlateCommon - Reference: 602; IsExternal: no; LoadBearing: no

# IfcPlate: Grate_Step#59 (2)
In: Default Storey
Description: -; Material: S235JR 3 mm
Pset_PlateCommon - Reference: 602; IsExternal: no; LoadBearing: no

# IfcPlate: Grate_Step#8 (12)
In: Default Storey
Description: -; Material: S235JR 40 mm
Pset_PlateCommon - Reference: 94; IsExternal: no; LoadBearing: no

# IfcPlate: Grate_Step#9 (12)
In: Default Storey
Description: -; Material: S235JR 3 mm
Pset_PlateCommon - Reference: 602; IsExternal: no; LoadBearing: no

# IfcPlate: Plate#500 (18)
In: Default Storey
Description: -; Material: S235JR 20 mm
Pset_PlateCommon - Reference: 544; IsExternal: no; LoadBearing: no

# IfcPlate: Plate#501 (18)
In: Default Storey
Description: -; Material: S235JR 20 mm
Pset_PlateCommon - Reference: 544; IsExternal: no; LoadBearing: no

# IfcPlate: Plate#502 (18)
In: Default Storey
Description: -; Material: S235JR 20 mm
Pset_PlateCommon - Reference: 544; IsExternal: no; LoadBearing: no

# IfcPlate: Plate#503 (10)
In: Default Storey
Description: -; Material: S235JR 20 mm
Pset_PlateCommon - Reference: 544; IsExternal: no; LoadBearing: no

# IfcPlate: Plate#504 (7)
In: Default Storey
Description: -; Material: S235JR 20 mm
Pset_PlateCommon - Reference: 544; IsExternal: no; LoadBearing: no

# IfcPlate: Plate#505 (6)
In: Default Storey
Description: -; Material: S235JR 20 mm
Pset_PlateCommon - Reference: 544; IsExternal: no; LoadBearing: no

# IfcPlate: Plate#506 (6)
In: Default Storey
Description: -; Material: S235JR 20 mm
Pset_PlateCommon - Reference: 544; IsExternal: no; LoadBearing: no

# IfcPlate: Plate#507 (6)
In: Default Storey
Description: -; Material: S235JR 20 mm
Pset_PlateCommon - Reference: 544; IsExternal: no; LoadBearing: no

# IfcPlate: Plate#508 (6)
In: Default Storey
Description: -; Material: S235JR 20 mm
Pset_PlateCommon - Reference: 544; IsExternal: no; LoadBearing: no

# IfcPlate: Plate#509 (6)
In: Default Storey
Description: -; Material: S235JR 20 mm
Pset_PlateCommon - Reference: 544; IsExternal: no; LoadBearing: no

# IfcPlate: Plate#510 (6)
In: Default Storey
Description: -; Material: S235JR 20 mm
Pset_PlateCommon - Reference: 544; IsExternal: no; LoadBearing: no

# IfcPlate: Plate#511 (6)
In: Default Storey
Description: -; Material: S235JR 20 mm
Pset_PlateCommon - Reference: 544; IsExternal: no; LoadBearing: no

# IfcPlate: Plate#512 (6)
In: Default Storey
Description: -; Material: S235JR 20 mm
Pset_PlateCommon - Reference: 544; IsExternal: no; LoadBearing: no

# IfcPlate: Plate#513 (6)
In: Default Storey
Description: -; Material: S235JR 20 mm
Pset_PlateCommon - Reference: 544; IsExternal: no; LoadBearing: no

# IfcPlate: Plate#514 (5)
In: Default Storey
Description: -; Material: S235JR 20 mm
Pset_PlateCommon - Reference: 544; IsExternal: no; LoadBearing: no

# IfcPlate: Stiffener#0 (23)
In: Default Storey
Description: -; Material: S235JR 10 mm
Pset_PlateCommon - Reference: 320; IsExternal: no; LoadBearing: no

# IfcPlate: Stiffener#1 (129)
In: Default Storey
Description: -; Material: S235JR 10 mm
Pset_PlateCommon - IsExternal: no; LoadBearing: no
Name | Reference
82 x Stiffener#1 | 343
24 x Stiffener#1 | 301
23 x Stiffener#1 | 320

# IfcPlate: Stiffener#2 (24)
In: Default Storey
Description: -; Material: S235JR 10 mm
Pset_PlateCommon - Reference: 301; IsExternal: no; LoadBearing: no

# IfcPlate: Stiffener#3 (24)
In: Default Storey
Description: -; Material: S235JR 10 mm
Pset_PlateCommon - Reference: 301; IsExternal: no; LoadBearing: no

# IfcPlate: Stiffener#4 (24)
In: Default Storey
Description: -; Material: S235JR 10 mm
Pset_PlateCommon - Reference: 301; IsExternal: no; LoadBearing: no

# IfcPlate: TopCoverGrate (23)
In: Default Storey
Description: -; Material: S235JR 40 mm
Pset_PlateCommon - IsExternal: no; LoadBearing: no
Name | Reference
2 x TopCoverGrate | 103
TopCoverGrate | 107
6 x TopCoverGrate | 95
TopCoverGrate | 108
5 x TopCoverGrate | 97
4 x TopCoverGrate | 99
4 x TopCoverGrate | 100

# IfcSlab: - (15)
In: Default Storey
Description: -
Pset_SlabCommon - Reference: nicht definiert; IsExternal: no; LoadBearing: no; Combustible: no; Compartmentation: no; PitchAngle: 0 deg
Name | Material
5 x - | C25/30 130 mm
6 x - | C25/30 60 mm
- | C25/30 170 mm
- | C25/30 120 mm
2 x - | C25/30 80 mm

# IfcWall: - (9)
In: Default Storey
Description: -
Pset_WallCommon - Reference: nicht definiert; Combustible: no; IsExternal: no; ExtendToStructure: no; LoadBearing: no; Compartmentation: no
Name | Material
- | C25/30 2272 mm
8 x - | C25/30 2400 mm
